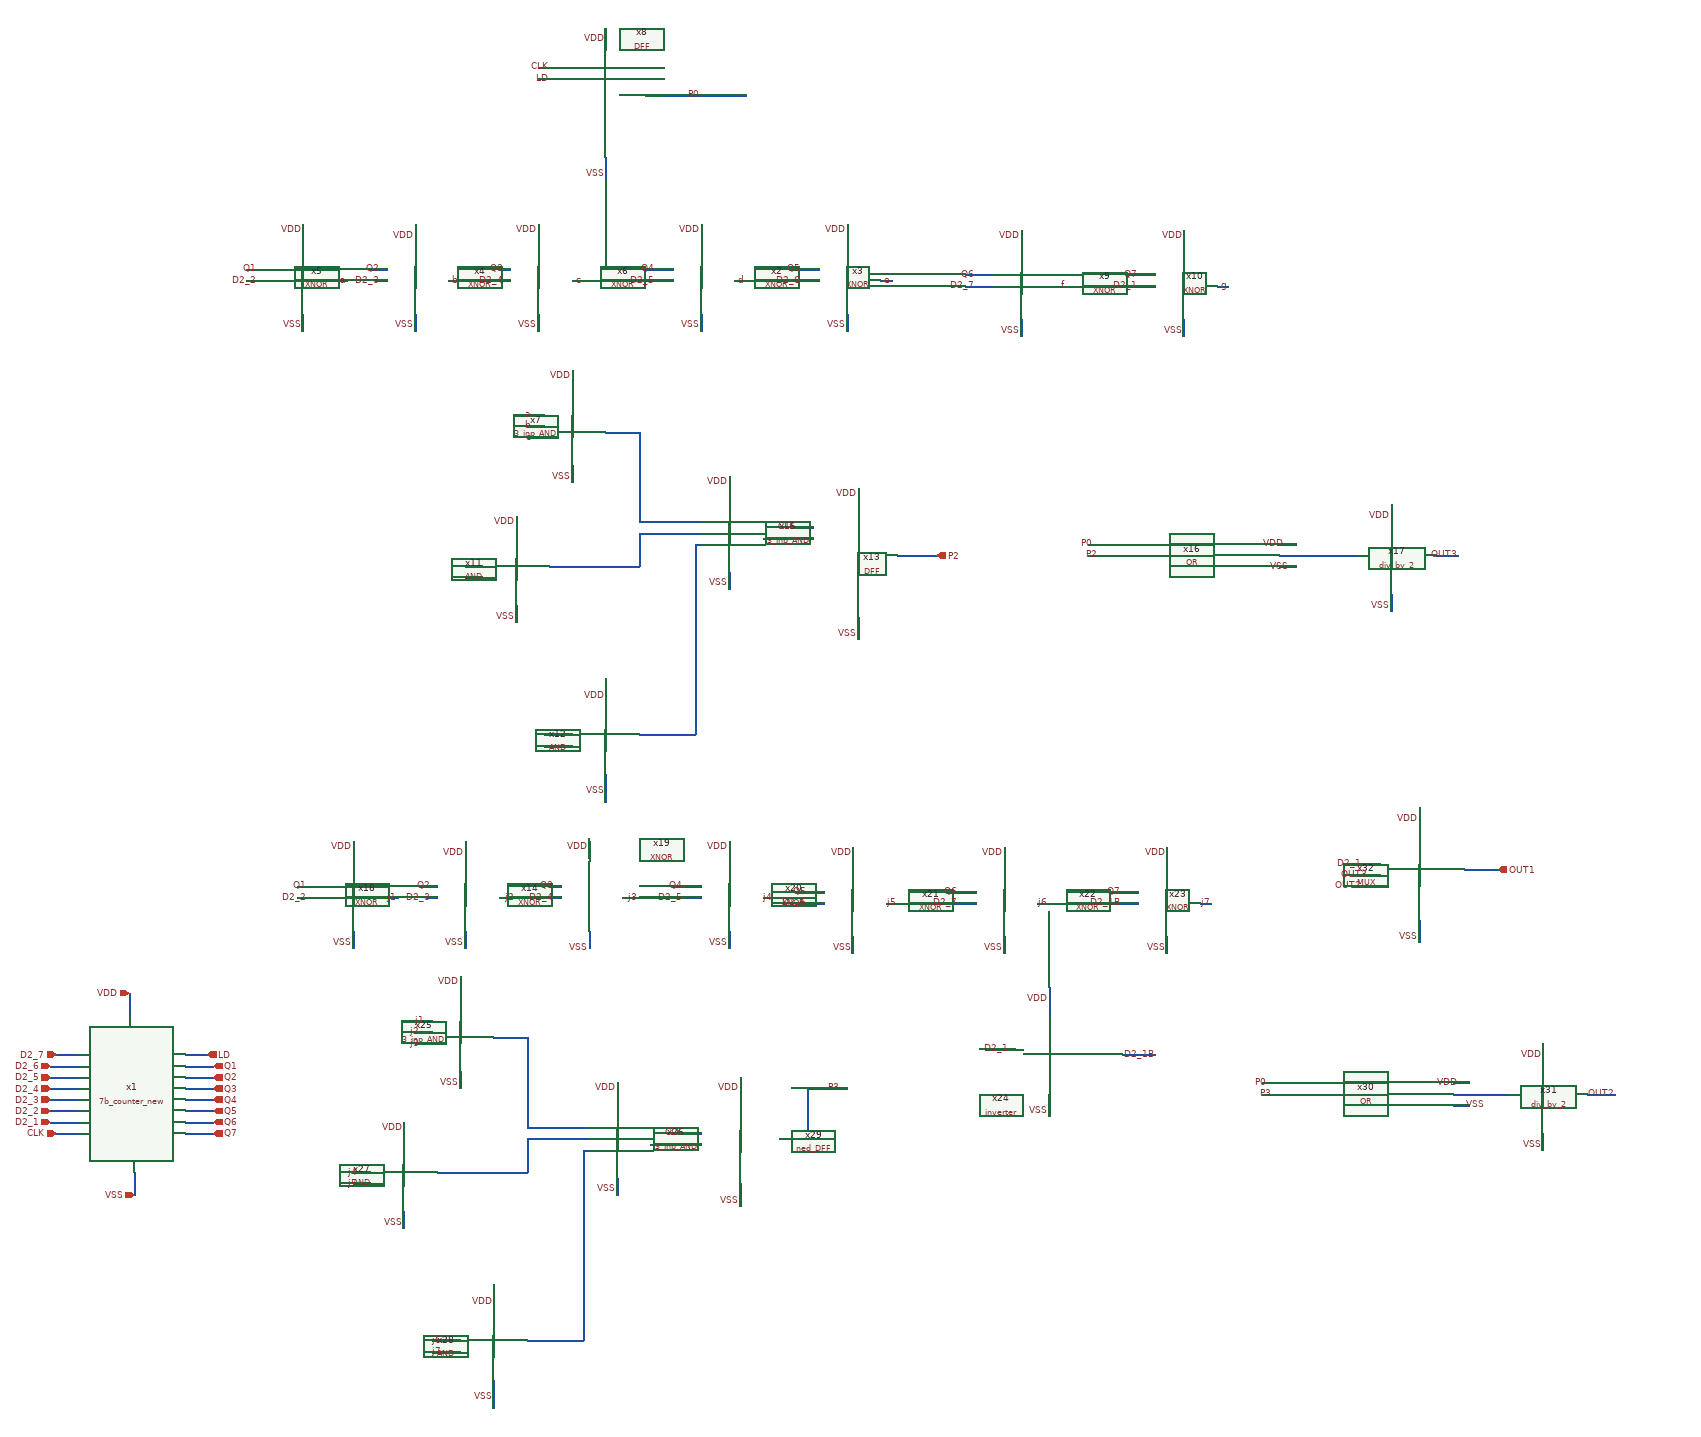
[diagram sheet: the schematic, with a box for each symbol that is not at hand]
v {xschem version=3.1.0 file_version=1.2
}
G {}
K {}
V {}
S {}
E {}
N 1140 -760 1140 -720 {
lab=VDD}
N 1150 -440 1150 -400 {
lab=VSS}
N 1010 -510 1050 -510 {
lab=CLK}
N 1240 -650 1280 -650 {
lab=LD}
N 1000 -530 1050 -530 {
lab=D2_1}
N 1000 -570 1050 -570 {
lab=D2_3}
N 1000 -550 1050 -550 {
lab=D2_2}
N 1000 -590 1050 -590 {
lab=D2_4}
N 1000 -610 1050 -610 {
lab=D2_5}
N 1000 -630 1050 -630 {
lab=D2_6}
N 1010 -650 1050 -650 {
lab=D2_7}
N 1240 -630 1290 -630 {
lab=Q1}
N 1240 -610 1290 -610 {
lab=Q2}
N 1240 -590 1290 -590 {
lab=Q3}
N 1240 -570 1290 -570 {
lab=Q4}
N 1240 -550 1290 -550 {
lab=Q5}
N 1240 -530 1290 -530 {
lab=Q6}
N 1240 -510 1290 -510 {
lab=Q7}
N 1350 -2050 1400 -2050 {
lab=Q1}
N 1350 -2030 1400 -2030 {
lab=D2_2}
N 1570 -2050 1600 -2050 {
lab=Q2}
N 1580 -2030 1600 -2030 {
lab=D2_3}
N 1800 -2050 1820 -2050 {
lab=Q3}
N 1800 -2030 1820 -2030 {
lab=D2_4}
N 1710 -2030 1740 -2030 {
lab=b}
N 1450 -2130 1450 -2100 {
lab=VDD}
N 1450 -1970 1450 -1940 {
lab=VSS}
N 1650 -2130 1650 -2100 {
lab=VDD}
N 1650 -1970 1650 -1940 {
lab=VSS}
N 1870 -2130 1870 -2100 {
lab=VDD}
N 1870 -1970 1870 -1940 {
lab=VSS}
N 1930 -2030 1960 -2030 {
lab=c}
N 1510 -2030 1530 -2030 {
lab=a}
N 1850 -1790 1880 -1790 {
lab=a}
N 1850 -1770 1880 -1770 {
lab=b}
N 1850 -1750 1880 -1750 {
lab=c}
N 1930 -1870 1930 -1840 {
lab=VDD}
N 2510 -1540 2580 -1540 {
lab=P2}
N 2060 -2050 2110 -2050 {
lab=Q4}
N 2060 -2030 2110 -2030 {
lab=D2_5}
N 2160 -2130 2160 -2100 {
lab=VDD}
N 2160 -1970 2160 -1940 {
lab=VSS}
N 2220 -2030 2240 -2030 {
lab=d}
N 2320 -2050 2370 -2050 {
lab=Q5}
N 2320 -2030 2370 -2030 {
lab=D2_6}
N 2420 -2130 2420 -2100 {
lab=VDD}
N 2420 -1970 2420 -1940 {
lab=VSS}
N 2480 -2030 2500 -2030 {
lab=e}
N 2630 -2040 2680 -2040 {
lab=Q6}
N 2630 -2020 2680 -2020 {
lab=D2_7}
N 2730 -2120 2730 -2090 {
lab=VDD}
N 2730 -1960 2730 -1930 {
lab=VSS}
N 2790 -2020 2810 -2020 {
lab=f}
N 2920 -2040 2970 -2040 {
lab=Q7}
N 2920 -2020 2970 -2020 {
lab=D2_1}
N 3020 -2120 3020 -2090 {
lab=VDD}
N 3020 -1960 3020 -1930 {
lab=VSS}
N 3080 -2020 3100 -2020 {
lab=g}
N 1930 -1700 1930 -1670 {
lab=VSS}
N 1740 -1520 1770 -1520 {
lab=d}
N 1740 -1500 1770 -1500 {
lab=e}
N 1830 -1610 1830 -1580 {
lab=VDD}
N 1830 -1450 1830 -1420 {
lab=VSS}
N 1990 -1320 1990 -1280 {
lab=VDD}
N 1990 -1150 1990 -1100 {
lab=VSS}
N 1880 -1220 1930 -1220 {
lab=g}
N 1880 -1200 1930 -1200 {
lab=f}
N 2130 -1600 2160 -1600 {
lab=#net1}
N 2130 -1580 2160 -1580 {
lab=#net2}
N 2210 -1680 2210 -1650 {
lab=VDD}
N 2210 -1510 2210 -1480 {
lab=VSS}
N 1990 -1760 2050 -1760 {
lab=#net1}
N 2050 -1760 2050 -1600 {
lab=#net1}
N 2050 -1600 2130 -1600 {
lab=#net1}
N 1980 -1520 2050 -1520 {
lab=#net2}
N 2050 -1580 2050 -1520 {
lab=#net2}
N 2050 -1580 2130 -1580 {
lab=#net2}
N 2150 -1560 2160 -1560 {
lab=#net3}
N 2270 -1570 2330 -1570 {
lab=#net4}
N 2850 -1560 2890 -1560 {
lab=P0}
N 2850 -1540 2890 -1540 {
lab=P2}
N 3190 -1560 3220 -1560 {
lab=VDD}
N 3190 -1520 3220 -1520 {
lab=VSS}
N 3280 -1540 3330 -1540 {
lab=#net5}
N 3390 -1630 3390 -1600 {
lab=VDD}
N 3390 -1470 3390 -1440 {
lab=VSS}
N 3470 -1540 3510 -1540 {
lab=OUT3}
N 2150 -1560 2150 -1220 {
lab=#net3}
N 1890 -1520 1980 -1520 {
lab=#net2}
N 2050 -1220 2150 -1220 {
lab=#net3}
N 1990 -2480 1990 -2440 {
lab=VDD}
N 1990 -2250 1990 -2210 {
lab=VSS}
N 1870 -2410 1910 -2410 {
lab=CLK}
N 1870 -2390 1910 -2390 {
lab=LD}
N 2060 -2360 2100 -2360 {
lab=P0}
N 2440 -1660 2440 -1620 {
lab=VDD}
N 2440 -1430 2440 -1390 {
lab=VSS}
N 2320 -1590 2360 -1590 {
lab=CLK}
N 2330 -1570 2360 -1570 {
lab=#net4}
N 1440 -950 1490 -950 {
lab=Q1}
N 1440 -930 1490 -930 {
lab=D2_2}
N 1660 -950 1690 -950 {
lab=Q2}
N 1670 -930 1690 -930 {
lab=D2_3}
N 1890 -950 1910 -950 {
lab=Q3}
N 1890 -930 1910 -930 {
lab=D2_4}
N 1800 -930 1830 -930 {
lab=j2}
N 1540 -1030 1540 -1000 {
lab=VDD}
N 1540 -870 1540 -840 {
lab=VSS}
N 1740 -1030 1740 -1000 {
lab=VDD}
N 1740 -870 1740 -840 {
lab=VSS}
N 1960 -1030 1960 -1000 {
lab=VDD}
N 1960 -870 1960 -840 {
lab=VSS}
N 2020 -930 2050 -930 {
lab=j3}
N 1600 -930 1620 -930 {
lab=j1}
N 2110 -950 2160 -950 {
lab=Q4}
N 2110 -930 2160 -930 {
lab=D2_5}
N 2210 -1030 2210 -1000 {
lab=VDD}
N 2210 -870 2210 -840 {
lab=VSS}
N 2270 -930 2290 -930 {
lab=j4}
N 2330 -940 2380 -940 {
lab=Q5}
N 2330 -920 2380 -920 {
lab=D2_6}
N 2430 -1020 2430 -990 {
lab=VDD}
N 2430 -860 2430 -830 {
lab=VSS}
N 2490 -920 2510 -920 {
lab=j5}
N 2600 -940 2650 -940 {
lab=Q6}
N 2600 -920 2650 -920 {
lab=D2_7}
N 2700 -1020 2700 -990 {
lab=VDD}
N 2700 -860 2700 -830 {
lab=VSS}
N 2760 -920 2780 -920 {
lab=j6}
N 2890 -940 2940 -940 {
lab=Q7}
N 2890 -920 2940 -920 {
lab=D2_1B}
N 2990 -1020 2990 -990 {
lab=VDD}
N 2990 -860 2990 -830 {
lab=VSS}
N 3050 -920 3070 -920 {
lab=j7}
N 2910 -650 2970 -650 {
lab=D2_1B}
N 2670 -660 2720 -660 {
lab=D2_1}
N 2780 -770 2780 -720 {
lab=VDD}
N 2780 -580 2780 -540 {
lab=VSS}
N 1650 -710 1680 -710 {
lab=j1}
N 1650 -690 1680 -690 {
lab=j2}
N 1650 -670 1680 -670 {
lab=j3}
N 1730 -790 1730 -760 {
lab=VDD}
N 2350 -590 2420 -590 {
lab=P3}
N 1730 -620 1730 -590 {
lab=VSS}
N 1540 -440 1570 -440 {
lab=j4}
N 1540 -420 1570 -420 {
lab=j5}
N 1630 -530 1630 -500 {
lab=VDD}
N 1630 -370 1630 -340 {
lab=VSS}
N 1790 -240 1790 -200 {
lab=VDD}
N 1790 -70 1790 -20 {
lab=VSS}
N 1680 -140 1730 -140 {
lab=j6}
N 1680 -120 1730 -120 {
lab=j7}
N 1930 -520 1960 -520 {
lab=#net6}
N 1930 -500 1960 -500 {
lab=#net7}
N 2010 -600 2010 -570 {
lab=VDD}
N 2010 -430 2010 -400 {
lab=VSS}
N 1790 -680 1850 -680 {
lab=#net6}
N 1850 -680 1850 -520 {
lab=#net6}
N 1850 -520 1930 -520 {
lab=#net6}
N 1780 -440 1850 -440 {
lab=#net7}
N 1850 -500 1850 -440 {
lab=#net7}
N 1850 -500 1930 -500 {
lab=#net7}
N 1950 -480 1960 -480 {
lab=#net8}
N 2070 -490 2130 -490 {
lab=#net9}
N 1950 -480 1950 -140 {
lab=#net8}
N 1690 -440 1780 -440 {
lab=#net7}
N 1850 -140 1950 -140 {
lab=#net8}
N 2350 -570 2350 -510 {
lab=P3}
N 2230 -610 2230 -570 {
lab=VDD}
N 2230 -420 2230 -380 {
lab=VSS}
N 2120 -510 2160 -510 {
lab=CLK}
N 2300 -500 2340 -500 {
lab=P3}
N 2130 -490 2160 -490 {
lab=#net9}
N 2340 -500 2350 -500 {
lab=P3}
N 2350 -510 2350 -500 {
lab=P3}
N 2350 -590 2350 -570 {
lab=P3}
N 3160 -600 3200 -600 {
lab=P0}
N 3160 -580 3200 -580 {
lab=P3}
N 3500 -600 3530 -600 {
lab=VDD}
N 3660 -510 3660 -480 {
lab=VSS}
N 3740 -580 3790 -580 {
lab=#net10}
N 3660 -670 3660 -640 {
lab=VDD}
N 3500 -560 3530 -560 {
lab=VSS}
N 3500 -580 3540 -580 {
lab=OUT2}
N 3440 -1090 3440 -1050 {
lab=VDD}
N 3440 -890 3440 -850 {
lab=VSS}
N 3320 -990 3370 -990 {
lab=D2_1}
N 3320 -970 3370 -970 {
lab=OUT3}
N 3320 -950 3370 -950 {
lab=OUT2}
N 3520 -980 3580 -980 {
lab=OUT1}
N 2100 -2360 2150 -2360 {
lab=P0}
N 2200 -2360 2240 -2360 {
lab=P0}
N 2150 -2360 2200 -2360 {
lab=P0}
N 3540 -580 3600 -580 {}
N 3190 -1540 3280 -1540 {}
C {devices/iopin.sym} 1140 -760 3 0 {name=p1 lab=VDD}
C {devices/iopin.sym} 1150 -400 1 0 {name=p2 lab=VSS}
C {devices/ipin.sym} 1000 -530 0 0 {name=p3 lab=D2_1}
C {devices/ipin.sym} 1010 -510 0 0 {name=p4 lab=CLK}
C {devices/ipin.sym} 1000 -550 0 0 {name=p5 lab=D2_2}
C {devices/ipin.sym} 1000 -570 0 0 {name=p6 lab=D2_3}
C {devices/ipin.sym} 1000 -590 0 0 {name=p7 lab=D2_4}
C {devices/ipin.sym} 1000 -610 0 0 {name=p8 lab=D2_5}
C {devices/ipin.sym} 1000 -630 0 0 {name=p9 lab=D2_6}
C {devices/ipin.sym} 1010 -650 0 0 {name=p10 lab=D2_7}
C {devices/opin.sym} 1280 -650 0 0 {name=p12 lab=LD}
C {devices/opin.sym} 1290 -630 0 0 {name=p13 lab=Q1}
C {devices/opin.sym} 1290 -610 0 0 {name=p14 lab=Q2}
C {devices/opin.sym} 1290 -590 0 0 {name=p15 lab=Q3}
C {devices/opin.sym} 1290 -570 0 0 {name=p16 lab=Q4}
C {devices/opin.sym} 1290 -550 0 0 {name=p17 lab=Q5}
C {devices/opin.sym} 1290 -530 0 0 {name=p18 lab=Q6}
C {devices/opin.sym} 1290 -510 0 0 {name=p19 lab=Q7}
C {XNOR.sym} 1750 -2030 0 0 {name=x4}
C {XNOR.sym} 1550 -2030 0 0 {name=x5}
C {XNOR.sym} 1970 -2030 0 0 {name=x6}
C {devices/lab_wire.sym} 1450 -2120 0 0 {name=p21 sig_type=std_logic lab=VDD}
C {devices/lab_wire.sym} 1650 -2110 0 0 {name=p22 sig_type=std_logic lab=VDD}
C {devices/lab_wire.sym} 1870 -2120 0 0 {name=p23 sig_type=std_logic lab=VDD}
C {devices/lab_wire.sym} 1450 -1950 0 0 {name=p24 sig_type=std_logic lab=VSS}
C {devices/lab_wire.sym} 1650 -1950 0 0 {name=p25 sig_type=std_logic lab=VSS}
C {devices/lab_wire.sym} 1930 -1680 0 0 {name=p26 sig_type=std_logic lab=VSS}
C {devices/lab_wire.sym} 1370 -2050 0 0 {name=p27 sig_type=std_logic lab=Q1}
C {devices/lab_wire.sym} 1590 -2050 0 0 {name=p28 sig_type=std_logic lab=Q2}
C {devices/lab_wire.sym} 1810 -2050 0 0 {name=p29 sig_type=std_logic lab=Q3}
C {devices/lab_wire.sym} 1810 -2030 0 0 {name=p30 sig_type=std_logic lab=D2_4}
C {devices/lab_wire.sym} 1590 -2030 0 0 {name=p31 sig_type=std_logic lab=D2_3}
C {devices/lab_wire.sym} 1370 -2030 0 0 {name=p32 sig_type=std_logic lab=D2_2}
C {3_inp_AND.sym} 2030 -1770 0 0 {name=x7}
C {devices/lab_wire.sym} 1930 -1860 0 0 {name=p33 sig_type=std_logic lab=VDD}
C {devices/lab_wire.sym} 1530 -2030 0 0 {name=p35 sig_type=std_logic lab=a}
C {devices/lab_wire.sym} 1730 -2030 0 0 {name=p36 sig_type=std_logic lab=b}
C {devices/lab_wire.sym} 1950 -2030 0 0 {name=p37 sig_type=std_logic lab=c}
C {devices/lab_wire.sym} 1860 -1790 0 0 {name=p38 sig_type=std_logic lab=a}
C {devices/opin.sym} 2580 -1540 0 0 {name=p43 lab=P2}
C {XNOR.sym} 2260 -2030 0 0 {name=x2}
C {devices/lab_wire.sym} 2160 -2120 0 0 {name=p45 sig_type=std_logic lab=VDD}
C {devices/lab_wire.sym} 2160 -1950 0 0 {name=p46 sig_type=std_logic lab=VSS}
C {devices/lab_wire.sym} 2080 -2050 0 0 {name=p47 sig_type=std_logic lab=Q4}
C {devices/lab_wire.sym} 2080 -2030 0 0 {name=p48 sig_type=std_logic lab=D2_5}
C {devices/lab_wire.sym} 2240 -2030 0 0 {name=p49 sig_type=std_logic lab=d}
C {XNOR.sym} 2520 -2030 0 0 {name=x3}
C {devices/lab_wire.sym} 2420 -2120 0 0 {name=p50 sig_type=std_logic lab=VDD}
C {devices/lab_wire.sym} 2420 -1950 0 0 {name=p51 sig_type=std_logic lab=VSS}
C {devices/lab_wire.sym} 2340 -2050 0 0 {name=p52 sig_type=std_logic lab=Q5}
C {devices/lab_wire.sym} 2340 -2030 0 0 {name=p53 sig_type=std_logic lab=D2_6}
C {devices/lab_wire.sym} 2500 -2030 0 0 {name=p54 sig_type=std_logic lab=e}
C {XNOR.sym} 2830 -2020 0 0 {name=x9}
C {devices/lab_wire.sym} 2730 -2110 0 0 {name=p55 sig_type=std_logic lab=VDD}
C {devices/lab_wire.sym} 2730 -1940 0 0 {name=p56 sig_type=std_logic lab=VSS}
C {devices/lab_wire.sym} 2650 -2040 0 0 {name=p57 sig_type=std_logic lab=Q6}
C {devices/lab_wire.sym} 2650 -2020 0 0 {name=p58 sig_type=std_logic lab=D2_7}
C {devices/lab_wire.sym} 2810 -2020 0 0 {name=p59 sig_type=std_logic lab=f}
C {XNOR.sym} 3120 -2020 0 0 {name=x10}
C {devices/lab_wire.sym} 3020 -2110 0 0 {name=p60 sig_type=std_logic lab=VDD}
C {devices/lab_wire.sym} 3020 -1940 0 0 {name=p61 sig_type=std_logic lab=VSS}
C {devices/lab_wire.sym} 2940 -2040 0 0 {name=p62 sig_type=std_logic lab=Q7}
C {devices/lab_wire.sym} 3100 -2020 0 0 {name=p64 sig_type=std_logic lab=g}
C {devices/lab_wire.sym} 1830 -1430 0 0 {name=p34 sig_type=std_logic lab=VSS}
C {devices/lab_wire.sym} 1830 -1600 0 0 {name=p70 sig_type=std_logic lab=VDD}
C {devices/lab_wire.sym} 1750 -1520 0 0 {name=p71 sig_type=std_logic lab=d}
C {devices/lab_wire.sym} 1750 -1500 0 0 {name=p72 sig_type=std_logic lab=e}
C {devices/lab_wire.sym} 1890 -1220 0 0 {name=p75 sig_type=std_logic lab=f}
C {devices/lab_wire.sym} 1990 -1290 0 0 {name=p76 sig_type=std_logic lab=VDD}
C {devices/lab_wire.sym} 1990 -1120 0 0 {name=p77 sig_type=std_logic lab=VSS}
C {devices/lab_wire.sym} 2210 -1490 0 0 {name=p80 sig_type=std_logic lab=VSS}
C {3_inp_AND.sym} 2310 -1580 0 0 {name=x15}
C {devices/lab_wire.sym} 2210 -1670 0 0 {name=p81 sig_type=std_logic lab=VDD}
C {OR.sym} 3040 -1540 0 0 {name=x16}
C {devices/lab_wire.sym} 3200 -1560 1 0 {name=p84 sig_type=std_logic lab=VDD}
C {devices/lab_wire.sym} 3210 -1520 3 0 {name=p85 sig_type=std_logic lab=VSS}
C {div_by_2.sym} 3480 -1520 0 0 {name=x17}
C {devices/lab_wire.sym} 3390 -1610 0 0 {name=p86 sig_type=std_logic lab=VDD}
C {devices/lab_wire.sym} 3390 -1450 0 0 {name=p87 sig_type=std_logic lab=VSS}
C {devices/lab_wire.sym} 1860 -1770 0 0 {name=p94 sig_type=std_logic lab=b}
C {devices/lab_wire.sym} 1860 -1750 0 0 {name=p95 sig_type=std_logic lab=c}
C {devices/lab_wire.sym} 1890 -1200 0 0 {name=p39 sig_type=std_logic lab=g}
C {7b_counter_new.sym} 1200 -560 0 0 {name=x1}
C {devices/lab_wire.sym} 2940 -2020 0 0 {name=p11 sig_type=std_logic lab=D2_1}
C {AND.sym} 1920 -1500 0 0 {name=x11}
C {AND.sym} 2080 -1200 0 0 {name=x12}
C {devices/lab_wire.sym} 1890 -2390 0 0 {name=p20 sig_type=std_logic lab=LD}
C {DFF.sym} 2060 -2390 0 0 {name=x8}
C {devices/lab_wire.sym} 1990 -2460 0 0 {name=p40 sig_type=std_logic lab=VDD}
C {devices/lab_wire.sym} 1990 -2220 0 0 {name=p41 sig_type=std_logic lab=VSS}
C {devices/lab_wire.sym} 1890 -2410 0 0 {name=p42 sig_type=std_logic lab=CLK}
C {devices/lab_wire.sym} 2860 -1560 0 0 {name=p63 sig_type=std_logic lab=P0}
C {devices/lab_wire.sym} 2440 -1650 0 0 {name=p66 sig_type=std_logic lab=VDD}
C {devices/lab_wire.sym} 2440 -1400 0 0 {name=p67 sig_type=std_logic lab=VSS}
C {devices/lab_wire.sym} 2330 -1590 0 0 {name=p65 sig_type=std_logic lab=CLK}
C {XNOR.sym} 1840 -930 0 0 {name=x14}
C {XNOR.sym} 1640 -930 0 0 {name=x18}
C {XNOR.sym} 2060 -930 0 0 {name=x19}
C {devices/lab_wire.sym} 1540 -1020 0 0 {name=p68 sig_type=std_logic lab=VDD}
C {devices/lab_wire.sym} 1740 -1010 0 0 {name=p73 sig_type=std_logic lab=VDD}
C {devices/lab_wire.sym} 1960 -1020 0 0 {name=p74 sig_type=std_logic lab=VDD}
C {devices/lab_wire.sym} 1540 -850 0 0 {name=p78 sig_type=std_logic lab=VSS}
C {devices/lab_wire.sym} 1740 -850 0 0 {name=p79 sig_type=std_logic lab=VSS}
C {devices/lab_wire.sym} 1460 -950 0 0 {name=p82 sig_type=std_logic lab=Q1}
C {devices/lab_wire.sym} 1680 -950 0 0 {name=p89 sig_type=std_logic lab=Q2}
C {devices/lab_wire.sym} 1900 -950 0 0 {name=p90 sig_type=std_logic lab=Q3}
C {devices/lab_wire.sym} 1900 -930 0 0 {name=p91 sig_type=std_logic lab=D2_4}
C {devices/lab_wire.sym} 1680 -930 0 0 {name=p92 sig_type=std_logic lab=D2_3}
C {devices/lab_wire.sym} 1460 -930 0 0 {name=p93 sig_type=std_logic lab=D2_2}
C {devices/lab_wire.sym} 1620 -930 0 0 {name=p96 sig_type=std_logic lab=j1}
C {XNOR.sym} 2310 -930 0 0 {name=x20}
C {devices/lab_wire.sym} 2210 -1020 0 0 {name=p99 sig_type=std_logic lab=VDD}
C {devices/lab_wire.sym} 2210 -850 0 0 {name=p100 sig_type=std_logic lab=VSS}
C {devices/lab_wire.sym} 2130 -950 0 0 {name=p101 sig_type=std_logic lab=Q4}
C {devices/lab_wire.sym} 2130 -930 0 0 {name=p102 sig_type=std_logic lab=D2_5}
C {XNOR.sym} 2530 -920 0 0 {name=x21}
C {devices/lab_wire.sym} 2430 -1010 0 0 {name=p104 sig_type=std_logic lab=VDD}
C {devices/lab_wire.sym} 2430 -840 0 0 {name=p105 sig_type=std_logic lab=VSS}
C {devices/lab_wire.sym} 2350 -940 0 0 {name=p106 sig_type=std_logic lab=Q5}
C {devices/lab_wire.sym} 2350 -920 0 0 {name=p107 sig_type=std_logic lab=D2_6}
C {XNOR.sym} 2800 -920 0 0 {name=x22}
C {devices/lab_wire.sym} 2700 -1010 0 0 {name=p109 sig_type=std_logic lab=VDD}
C {devices/lab_wire.sym} 2700 -840 0 0 {name=p110 sig_type=std_logic lab=VSS}
C {devices/lab_wire.sym} 2620 -940 0 0 {name=p111 sig_type=std_logic lab=Q6}
C {devices/lab_wire.sym} 2620 -920 0 0 {name=p112 sig_type=std_logic lab=D2_7}
C {XNOR.sym} 3090 -920 0 0 {name=x23}
C {devices/lab_wire.sym} 2990 -1010 0 0 {name=p114 sig_type=std_logic lab=VDD}
C {devices/lab_wire.sym} 2990 -840 0 0 {name=p115 sig_type=std_logic lab=VSS}
C {devices/lab_wire.sym} 2910 -940 0 0 {name=p116 sig_type=std_logic lab=Q7}
C {devices/lab_wire.sym} 2910 -920 0 0 {name=p118 sig_type=std_logic lab=D2_1B}
C {inverter.sym} 2870 -640 0 0 {name=x24}
C {devices/lab_wire.sym} 2780 -750 0 0 {name=p119 sig_type=std_logic lab=VDD}
C {devices/lab_wire.sym} 2780 -550 0 0 {name=p120 sig_type=std_logic lab=VSS}
C {devices/lab_wire.sym} 2710 -660 0 0 {name=p121 sig_type=std_logic lab=D2_1}
C {devices/lab_wire.sym} 2970 -650 0 0 {name=p122 sig_type=std_logic lab=D2_1B}
C {devices/lab_wire.sym} 1830 -930 0 0 {name=p97 sig_type=std_logic lab=j2}
C {devices/lab_wire.sym} 2050 -930 0 0 {name=p98 sig_type=std_logic lab=j3}
C {devices/lab_wire.sym} 2290 -930 0 0 {name=p103 sig_type=std_logic lab=j4}
C {devices/lab_wire.sym} 2510 -920 0 0 {name=p108 sig_type=std_logic lab=j5}
C {devices/lab_wire.sym} 2780 -920 0 0 {name=p113 sig_type=std_logic lab=j6}
C {devices/lab_wire.sym} 3070 -920 0 0 {name=p117 sig_type=std_logic lab=j7}
C {devices/lab_wire.sym} 1730 -600 0 0 {name=p123 sig_type=std_logic lab=VSS}
C {3_inp_AND.sym} 1830 -690 0 0 {name=x25}
C {devices/lab_wire.sym} 1730 -780 0 0 {name=p124 sig_type=std_logic lab=VDD}
C {devices/lab_wire.sym} 1630 -350 0 0 {name=p127 sig_type=std_logic lab=VSS}
C {devices/lab_wire.sym} 1630 -520 0 0 {name=p128 sig_type=std_logic lab=VDD}
C {devices/lab_wire.sym} 1790 -210 0 0 {name=p132 sig_type=std_logic lab=VDD}
C {devices/lab_wire.sym} 1790 -40 0 0 {name=p133 sig_type=std_logic lab=VSS}
C {devices/lab_wire.sym} 2010 -410 0 0 {name=p134 sig_type=std_logic lab=VSS}
C {3_inp_AND.sym} 2110 -500 0 0 {name=x26}
C {devices/lab_wire.sym} 2010 -590 0 0 {name=p135 sig_type=std_logic lab=VDD}
C {AND.sym} 1720 -420 0 0 {name=x27}
C {AND.sym} 1880 -120 0 0 {name=x28}
C {devices/lab_wire.sym} 2230 -590 0 0 {name=p139 sig_type=std_logic lab=VDD}
C {devices/lab_wire.sym} 2230 -390 0 0 {name=p140 sig_type=std_logic lab=VSS}
C {devices/lab_wire.sym} 2410 -590 0 0 {name=p141 sig_type=std_logic lab=P3}
C {devices/lab_wire.sym} 2130 -510 0 0 {name=p142 sig_type=std_logic lab=CLK}
C {devices/lab_wire.sym} 1670 -710 0 0 {name=p125 sig_type=std_logic lab=j1}
C {devices/lab_wire.sym} 1660 -690 0 0 {name=p129 sig_type=std_logic lab=j2}
C {devices/lab_wire.sym} 1660 -670 0 0 {name=p130 sig_type=std_logic lab=j3}
C {devices/lab_wire.sym} 1550 -440 0 0 {name=p131 sig_type=std_logic lab=j4}
C {devices/lab_wire.sym} 1550 -420 0 0 {name=p136 sig_type=std_logic lab=j5}
C {devices/lab_wire.sym} 1700 -140 0 0 {name=p137 sig_type=std_logic lab=j6}
C {devices/lab_wire.sym} 1700 -120 0 0 {name=p138 sig_type=std_logic lab=j7}
C {ned_DFF.sym} 2310 -490 0 0 {name=x29}
C {OR.sym} 3350 -580 0 0 {name=x30}
C {devices/lab_wire.sym} 3180 -580 0 0 {name=p88 sig_type=std_logic lab=P3}
C {devices/lab_wire.sym} 3510 -600 1 0 {name=p126 sig_type=std_logic lab=VDD}
C {devices/lab_wire.sym} 3660 -490 0 0 {name=p143 sig_type=std_logic lab=VSS}
C {div_by_2.sym} 3750 -560 0 0 {name=x31}
C {devices/lab_wire.sym} 3660 -650 0 0 {name=p144 sig_type=std_logic lab=VDD}
C {devices/lab_wire.sym} 3520 -560 2 0 {name=p145 sig_type=std_logic lab=VSS}
C {devices/lab_wire.sym} 3170 -600 0 0 {name=p146 sig_type=std_logic lab=P0}
C {devices/lab_wire.sym} 3790 -580 0 0 {name=p147 sig_type=std_logic lab=OUT2}
C {devices/opin.sym} 3580 -980 0 0 {name=p69 lab=OUT1}
C {devices/lab_wire.sym} 1960 -840 0 0 {name=p148 sig_type=std_logic lab=VSS}
C {MUX.sym} 3520 -970 0 0 {name=x32}
C {devices/lab_wire.sym} 3340 -990 0 0 {name=p149 sig_type=std_logic lab=D2_1}
C {devices/lab_wire.sym} 3510 -1540 0 0 {name=p150 sig_type=std_logic lab=OUT3}
C {devices/lab_wire.sym} 3350 -970 0 0 {name=p151 sig_type=std_logic lab=OUT3}
C {devices/lab_wire.sym} 3340 -950 0 0 {name=p152 sig_type=std_logic lab=OUT2}
C {devices/lab_wire.sym} 3440 -1070 0 0 {name=p153 sig_type=std_logic lab=VDD}
C {devices/lab_wire.sym} 3440 -860 0 0 {name=p154 sig_type=std_logic lab=VSS}
C {DFF.sym} 2510 -1570 0 0 {name=x13}
C {devices/lab_wire.sym} 2160 -2360 0 0 {name=p165 sig_type=std_logic lab=P0}
C {devices/lab_wire.sym} 2870 -1540 0 0 {name=p44 sig_type=std_logic lab=P2}
C {devices/lab_wire.sym} 1870 -1950 0 0 {name=p83 sig_type=std_logic lab=VSS}
